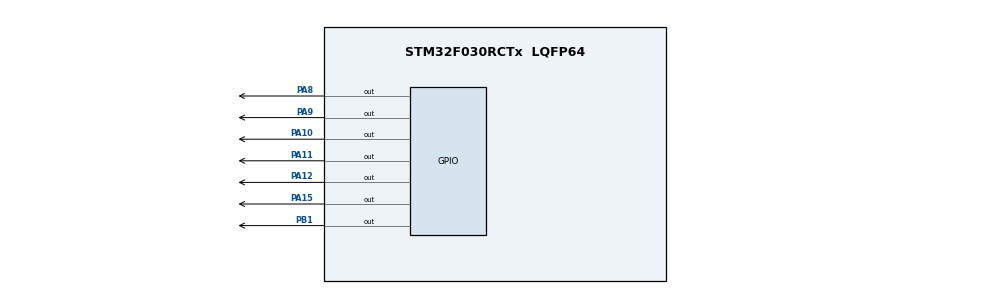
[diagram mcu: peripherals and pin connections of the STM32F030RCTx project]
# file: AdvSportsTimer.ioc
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Mcu.Family=STM32F0
Mcu.Name=STM32F030RCTx
Mcu.Package=LQFP64
PA10.Signal=GPIO_Output
PA11.Signal=GPIO_Output
PA12.Signal=GPIO_Output
PA13.Mode=Serial_Wire
PA13.Signal=SYS_SWDIO
PA14.Mode=Serial_Wire
PA14.Signal=SYS_SWCLK
PA15.Signal=GPIO_Output
PA8.Signal=GPIO_Output
PA9.Signal=GPIO_Output
PB1.Signal=GPIO_Output
ProjectManager.HeapSize=0x200
ProjectManager.StackSize=0x400
ProjectManager.TargetToolchain=MDK-ARM V5
board=AdvSportsTimer

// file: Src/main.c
/**
  ******************************************************************************
  * File Name          : main.c
  * Description        : Main program body
  ******************************************************************************
  *
  * COPYRIGHT(c) 2017 STMicroelectronics
  *
  * Redistribution and use in source and binary forms, with or without modification,
  * are permitted provided that the following conditions are met:
  *   1. Redistributions of source code must retain the above copyright notice,
  *      this list of conditions and the following disclaimer.
  *   2. Redistributions in binary form must reproduce the above copyright notice,
  *      this list of conditions and the following disclaimer in the documentation
  *      and/or other materials provided with the distribution.
  *   3. Neither the name of STMicroelectronics nor the names of its contributors
  *      may be used to endorse or promote products derived from this software
  *      without specific prior written permission.
  *
  * THIS SOFTWARE IS PROVIDED BY THE COPYRIGHT HOLDERS AND CONTRIBUTORS "AS IS"
  * AND ANY EXPRESS OR IMPLIED WARRANTIES, INCLUDING, BUT NOT LIMITED TO, THE
  * IMPLIED WARRANTIES OF MERCHANTABILITY AND FITNESS FOR A PARTICULAR PURPOSE ARE
  * DISCLAIMED. IN NO EVENT SHALL THE COPYRIGHT HOLDER OR CONTRIBUTORS BE LIABLE
  * FOR ANY DIRECT, INDIRECT, INCIDENTAL, SPECIAL, EXEMPLARY, OR CONSEQUENTIAL
  * DAMAGES (INCLUDING, BUT NOT LIMITED TO, PROCUREMENT OF SUBSTITUTE GOODS OR
  * SERVICES; LOSS OF USE, DATA, OR PROFITS; OR BUSINESS INTERRUPTION) HOWEVER
  * CAUSED AND ON ANY THEORY OF LIABILITY, WHETHER IN CONTRACT, STRICT LIABILITY,
  * OR TORT (INCLUDING NEGLIGENCE OR OTHERWISE) ARISING IN ANY WAY OUT OF THE USE
  * OF THIS SOFTWARE, EVEN IF ADVISED OF THE POSSIBILITY OF SUCH DAMAGE.
  *
  ******************************************************************************
  */
#include "main.h"
#include "stm32f0xx_hal.h"
#include "stm32f0xx_it.h"
#include "stm32f0xx_hal_spi.h"
#include "LCD_config.h"
#include "timing.h"
#include "buttons.h"
#include "rf430_reg.h"

/* USER CODE BEGIN PV */
/* Private variables ---------------------------------------------------------*/
SPI_HandleTypeDef hspi1;
extern Mode timer_mode;
extern volatile unsigned int clear_screen_flag, time_up_flag;
uint8_t NDEF_data[] = RF430_DEFAULT_DATA;
uint16_t curr_location = 35; //The current size of the default data is 35
uint8_t filelength[2] = {0x00, 0x07}; //NDEF file length for location A26 and A27
uint8_t payloadlength[1] = {0x03}; //payload file length for location A30. To send larger messages you can't use a short record

/* USER CODE END PV */

void SystemClock_Config(void);
void Error_Handler(void);
static void MX_GPIO_Init(void);
static void MX_SPI1_Init(void);
static void RF430_init(void);
static uint16_t rf430_read_register( uint16_t register_addr);
static void rf430_write_register( uint16_t register_addr, uint16_t value);
static void rf430_write_continuous( uint16_t starting_addr, uint8_t * data, uint32_t data_length);

/* USER CODE BEGIN PFP */
/* Private function prototypes -----------------------------------------------*/

/* USER CODE END PFP */

int main(void)
{

  /* MCU Configuration----------------------------------------------------------*/

  /* Reset of all peripherals, Initializes the Flash interface and the Systick. */
  HAL_Init();

  /* Configure the system clock */
  SystemClock_Config();

  /* Initialize all configured peripherals */
  MX_GPIO_Init();
	HAL_GPIO_WritePin(GPIOA, GPIO_PIN_4, GPIO_PIN_SET);
	//MX_SPI1_Init();

	LCD_init();
	button_init();
	//RF430_init();

  /* Infinite loop */
  /* USER CODE BEGIN WHILE */
  while (1)
  {
		update_time_str();
		if(clear_screen_flag){
			clear_screen();
			clear_screen_flag = 0;
		}
		if(timer_mode){
			print_string(time_str);
			if(time_up_flag){
				time_up_flag = 0;
				move_cursor(64);
				print_string("Time's up!!");
			}
			move_cursor(14);
			print_byte('M');
			print_byte('2');
		}
		else{
			print_string(time_str);
			if(lap_flag){
				move_cursor(64);
				update_lap_str();
				print_string(lap_str);
			}
			move_cursor(14);
			print_byte('M');
			print_byte('1');
		}
		cursor_toHome();
  }
}

/** System Clock Configuration
*/
void SystemClock_Config(void)
{

  RCC_OscInitTypeDef RCC_OscInitStruct;
  RCC_ClkInitTypeDef RCC_ClkInitStruct;

    /**Initializes the CPU, AHB and APB busses clocks
    */
  RCC_OscInitStruct.OscillatorType = RCC_OSCILLATORTYPE_HSI;
  RCC_OscInitStruct.HSIState = RCC_HSI_ON;
  RCC_OscInitStruct.HSICalibrationValue = 16;
  RCC_OscInitStruct.PLL.PLLState = RCC_PLL_NONE;
  if (HAL_RCC_OscConfig(&RCC_OscInitStruct) != HAL_OK)
  {
    Error_Handler();
  }

    /**Initializes the CPU, AHB and APB busses clocks
    */
  RCC_ClkInitStruct.ClockType = RCC_CLOCKTYPE_HCLK|RCC_CLOCKTYPE_SYSCLK
                              |RCC_CLOCKTYPE_PCLK1;
  RCC_ClkInitStruct.SYSCLKSource = RCC_SYSCLKSOURCE_HSI;
  RCC_ClkInitStruct.AHBCLKDivider = RCC_SYSCLK_DIV1;
  RCC_ClkInitStruct.APB1CLKDivider = RCC_HCLK_DIV1;

  if (HAL_RCC_ClockConfig(&RCC_ClkInitStruct, FLASH_LATENCY_0) != HAL_OK)
  {
    Error_Handler();
  }

    /**Configure the Systick interrupt time
    */
  HAL_SYSTICK_Config(HAL_RCC_GetHCLKFreq()/1000);

    /**Configure the Systick
    */
  HAL_SYSTICK_CLKSourceConfig(SYSTICK_CLKSOURCE_HCLK);

  /* SysTick_IRQn interrupt configuration */
  HAL_NVIC_SetPriority(SysTick_IRQn, 0, 0);
}

/* SPI1 init function */
/*static void MX_SPI1_Init(void)
{

  hspi1.Instance = SPI1;
  hspi1.Init.Mode = SPI_MODE_MASTER;
  hspi1.Init.Direction = SPI_DIRECTION_2LINES;
  hspi1.Init.DataSize = SPI_DATASIZE_4BIT;
  hspi1.Init.CLKPolarity = SPI_POLARITY_LOW;
  hspi1.Init.CLKPhase = SPI_PHASE_1EDGE;
  hspi1.Init.NSS = SPI_NSS_SOFT;
  hspi1.Init.BaudRatePrescaler = SPI_BAUDRATEPRESCALER_4;
  hspi1.Init.FirstBit = SPI_FIRSTBIT_MSB;
  hspi1.Init.TIMode = SPI_TIMODE_DISABLE;
  hspi1.Init.CRCCalculation = SPI_CRCCALCULATION_DISABLE;
  hspi1.Init.CRCPolynomial = 7;
  hspi1.Init.CRCLength = SPI_CRC_LENGTH_DATASIZE;
  hspi1.Init.NSSPMode = SPI_NSS_PULSE_ENABLE;
  if (HAL_SPI_Init(&hspi1) != HAL_OK)
  {
    Error_Handler();
  }

}*/

/** Configure pins as
        * Analog
        * Input
        * Output
        * EVENT_OUT
        * EXTI
*/
static void MX_GPIO_Init(void)
{

  GPIO_InitTypeDef GPIO_InitStruct;

  /* GPIO Ports Clock Enable */
  __HAL_RCC_GPIOB_CLK_ENABLE();
  __HAL_RCC_GPIOA_CLK_ENABLE();

  /*Configure GPIO pin Output Level */
  HAL_GPIO_WritePin(GPIOB, GPIO_PIN_1, GPIO_PIN_RESET);

  /*Configure GPIO pin Output Level */
  HAL_GPIO_WritePin(GPIOA, GPIO_PIN_8|GPIO_PIN_9|GPIO_PIN_10|GPIO_PIN_11
                          |GPIO_PIN_12|GPIO_PIN_15 | GPIO_PIN_4, GPIO_PIN_RESET);

  /*Configure GPIO pin : PB1 */
  GPIO_InitStruct.Pin = GPIO_PIN_1;
  GPIO_InitStruct.Mode = GPIO_MODE_OUTPUT_PP;
  GPIO_InitStruct.Pull = GPIO_NOPULL;
  GPIO_InitStruct.Speed = GPIO_SPEED_FREQ_HIGH;
  HAL_GPIO_Init(GPIOB, &GPIO_InitStruct);

	/*Configure GPIO pin : PB0 */
  GPIO_InitStruct.Pin = GPIO_PIN_0;
  GPIO_InitStruct.Mode = GPIO_MODE_INPUT;
  GPIO_InitStruct.Pull = GPIO_NOPULL;
  HAL_GPIO_Init(GPIOB, &GPIO_InitStruct);

  /*Configure GPIO pins : PA8 PA9 PA10 PA11
                           PA12 PA15 PA4 */
  GPIO_InitStruct.Pin = GPIO_PIN_4 | GPIO_PIN_8|GPIO_PIN_9|GPIO_PIN_10|GPIO_PIN_11
                          |GPIO_PIN_12|GPIO_PIN_15;
  GPIO_InitStruct.Mode = GPIO_MODE_OUTPUT_PP;
  GPIO_InitStruct.Pull = GPIO_NOPULL;
  GPIO_InitStruct.Speed = GPIO_SPEED_FREQ_HIGH;
  HAL_GPIO_Init(GPIOA, &GPIO_InitStruct);

}

/* USER CODE BEGIN 4 */
static void RF430_init(){
	while(!(rf430_read_register(STATUS_REG) & NDEF_READY));
	rf430_write_continuous(0, NDEF_data, curr_location);
	rf430_write_register(CONTROL_REG, RF_ENABLE);
}

static uint16_t rf430_read_register( uint16_t register_addr){
	uint8_t high_nybble = (register_addr >> 4) & 0xFF;
	uint8_t low_nybble = register_addr & 0xFF;
	uint16_t ret_val = 0x0000;
	uint8_t instr = 0x03;
	//Bring down the cs pin
	HAL_GPIO_WritePin(GPIOA, GPIO_PIN_4,GPIO_PIN_RESET);
	HAL_SPI_Transmit(&hspi1, &instr, 1, 50);
	HAL_SPI_Transmit(&hspi1, &high_nybble, 1, 50);
	HAL_SPI_Transmit(&hspi1, &low_nybble, 1, 50);
	instr = 0xFF;//dummy byte
	HAL_SPI_Transmit(&hspi1, &instr, 1, 50);

	//now we recieve the information
	HAL_SPI_Receive(&hspi1, (uint8_t *)(&ret_val), 2, 50);

	//now we set the cs pin high again
	HAL_GPIO_WritePin(GPIOA, GPIO_PIN_4, GPIO_PIN_SET);
	return ret_val;
}

static void rf430_write_register( uint16_t register_addr, uint16_t value){
	uint8_t high_nybble = (register_addr >> 4) & 0xFF;
	uint8_t low_nybble = register_addr & 0xFF;
	uint8_t instr = 0x02;
	//Bring down the cs pin
	HAL_GPIO_WritePin(GPIOA, GPIO_PIN_4, GPIO_PIN_RESET);
	HAL_SPI_Transmit(&hspi1, &instr, 1, 50);
	HAL_SPI_Transmit(&hspi1, &high_nybble, 1, 50);
	HAL_SPI_Transmit(&hspi1, &low_nybble, 1, 50);
	//now we write the data
	HAL_SPI_Transmit(&hspi1, (uint8_t *)(&value), 2, 50);

	//Set the cs pin high again
	HAL_GPIO_WritePin(GPIOA, GPIO_PIN_4, GPIO_PIN_SET);
}

static void rf430_write_continuous( uint16_t starting_addr, uint8_t * data, uint32_t data_length){
	uint8_t high_nybble = (starting_addr >> 4) & 0xFF;
	uint8_t low_nybble = starting_addr & 0xFF;
	uint8_t instr = 0x02;
	//Bring down the cs pin
	HAL_GPIO_WritePin(GPIOA, GPIO_PIN_4, GPIO_PIN_RESET);
	HAL_SPI_Transmit(&hspi1, &instr, 1, 50);
	HAL_SPI_Transmit(&hspi1, &high_nybble, 1, 50);
	HAL_SPI_Transmit(&hspi1, &low_nybble, 1, 50);
	//Now we send the data
	HAL_SPI_Transmit(&hspi1, data, data_length, 50);

	HAL_GPIO_WritePin(GPIOA, GPIO_PIN_4, GPIO_PIN_SET);
}

/* USER CODE END 4 */

void Error_Handler(void)
{
  while(1)
  {
  }
}

/************************ (C) COPYRIGHT STMicroelectronics *****END OF FILE****/
